VERSION 5.8 ;
BUSBITCHARS "[]" ;
DIVIDERCHAR "/" ;
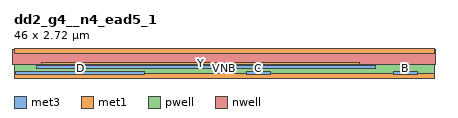
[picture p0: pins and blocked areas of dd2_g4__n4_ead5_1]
MACRO dd2_g4__n4_ead5_1
  CLASS CORE ;
  ORIGIN 0 0 ;
  SIZE 46.000 BY 2.720 ;
  SYMMETRY X Y ;
  SITE unithd ;
  PIN A
    DIRECTION INPUT ;
    USE SIGNAL ;
    ANTENNAGATEAREA 0.426000 ;
    PORT
      LAYER met3 ;
        RECT 2.485 0.855 39.615 1.185 ;
    END
  END A
  PIN B
    DIRECTION INPUT ;
    USE SIGNAL ;
    ANTENNAGATEAREA 0.213000 ;
    PORT
      LAYER met3 ;
        RECT 41.585 0.175 44.215 0.505 ;
    END
  END B
  PIN C
    DIRECTION INPUT ;
    USE SIGNAL ;
    ANTENNAGATEAREA 0.213000 ;
    PORT
      LAYER met3 ;
        RECT 25.485 0.175 28.115 0.505 ;
    END
  END C
  PIN D
    DIRECTION INPUT ;
    USE SIGNAL ;
    ANTENNAGATEAREA 0.426000 ;
    PORT
      LAYER met3 ;
        RECT 0.185 0.175 14.315 0.505 ;
    END
  END D
  PIN VGND
    DIRECTION INOUT ;
    USE GROUND ;
    SHAPE ABUTMENT ;
    PORT
      LAYER met1 ;
        RECT 0.000 -0.240 46.000 0.240 ;
    END
  END VGND
  PIN VNB
    DIRECTION INOUT ;
    USE GROUND ;
    PORT
      LAYER pwell ;
        RECT 0.000 0.000 46.000 1.305 ;
    END
  END VNB
  PIN VPB
    DIRECTION INOUT ;
    USE POWER ;
    PORT
      LAYER nwell ;
        RECT -0.190 1.305 46.190 2.910 ;
    END
  END VPB
  PIN VPWR
    DIRECTION INOUT ;
    USE POWER ;
    SHAPE ABUTMENT ;
    PORT
      LAYER met1 ;
        RECT 0.000 2.480 46.000 2.960 ;
    END
  END VPWR
  PIN Y
    DIRECTION OUTPUT ;
    USE SIGNAL ;
    ANTENNADIFFAREA 1.305600 ;
    PORT
      LAYER met1 ;
        RECT 3.065 1.230 3.385 1.290 ;
        RECT 9.965 1.230 10.285 1.290 ;
        RECT 12.265 1.230 12.585 1.290 ;
        RECT 19.165 1.230 19.485 1.290 ;
        RECT 37.565 1.230 37.885 1.290 ;
        RECT 3.060 1.290 37.890 1.430 ;
        RECT 3.065 1.430 3.385 1.490 ;
        RECT 9.965 1.430 10.285 1.490 ;
        RECT 12.265 1.430 12.585 1.490 ;
        RECT 19.165 1.430 19.485 1.490 ;
        RECT 37.565 1.430 37.885 1.490 ;
    END
  END Y
  OBS
    LAYER li1 ;
      RECT 0.000 -0.085 46.000 0.085 ;
      RECT 0.000 2.635 46.000 2.805 ;
      RECT 29.090 0.085 29.260 0.255 ;
      RECT 42.890 0.085 43.060 0.255 ;
      RECT 24.410 0.255 24.740 0.635 ;
      RECT 29.010 0.255 29.340 0.635 ;
      RECT 42.810 0.255 43.140 0.635 ;
      RECT 23.910 0.255 24.240 0.380 ;
      RECT 23.760 0.380 24.240 0.710 ;
      RECT 28.510 0.255 28.840 0.380 ;
      RECT 28.360 0.380 28.840 0.710 ;
      RECT 30.810 0.255 31.140 0.380 ;
      RECT 30.660 0.380 31.140 0.710 ;
      RECT 31.310 0.255 31.640 0.380 ;
      RECT 31.310 0.380 31.680 0.710 ;
      RECT 35.410 0.255 35.740 0.380 ;
      RECT 35.260 0.380 35.740 0.710 ;
      RECT 35.910 0.255 36.240 0.380 ;
      RECT 35.910 0.380 36.280 0.710 ;
      RECT 42.310 0.255 42.640 0.380 ;
      RECT 42.160 0.380 42.640 0.710 ;
      RECT 23.165 0.380 23.515 0.710 ;
      RECT 23.165 0.710 23.335 1.075 ;
      RECT 23.165 1.075 24.340 1.315 ;
      RECT 25.465 0.380 25.815 0.710 ;
      RECT 25.465 0.710 25.635 1.075 ;
      RECT 25.465 1.075 26.640 1.315 ;
      RECT 27.765 0.380 28.115 0.710 ;
      RECT 27.765 0.710 27.935 1.075 ;
      RECT 27.765 1.075 28.940 1.315 ;
      RECT 30.065 0.380 30.415 0.710 ;
      RECT 30.065 0.710 30.235 1.075 ;
      RECT 30.065 1.075 31.240 1.315 ;
      RECT 32.365 0.380 32.715 0.710 ;
      RECT 32.365 0.710 32.535 1.075 ;
      RECT 32.365 1.075 33.540 1.315 ;
      RECT 34.665 0.380 35.015 0.710 ;
      RECT 34.665 0.710 34.835 1.075 ;
      RECT 34.665 1.075 35.840 1.315 ;
      RECT 36.965 0.380 37.315 0.710 ;
      RECT 36.965 0.710 37.135 1.075 ;
      RECT 36.965 1.075 38.140 1.315 ;
      RECT 39.265 0.380 39.615 0.710 ;
      RECT 39.265 0.710 39.435 1.075 ;
      RECT 39.265 1.075 40.440 1.315 ;
      RECT 41.565 0.380 41.915 0.710 ;
      RECT 41.565 0.710 41.735 1.075 ;
      RECT 41.565 1.075 42.740 1.315 ;
      RECT 43.865 0.380 44.215 0.710 ;
      RECT 43.865 0.710 44.035 1.075 ;
      RECT 43.865 1.075 45.040 1.315 ;
      RECT 26.210 1.505 26.540 2.010 ;
      RECT 26.060 2.010 26.540 2.340 ;
      RECT 26.210 2.340 26.540 2.465 ;
      RECT 33.110 1.505 33.440 2.010 ;
      RECT 32.960 2.010 33.440 2.340 ;
      RECT 33.110 2.340 33.440 2.465 ;
      RECT 37.710 1.505 38.040 2.010 ;
      RECT 37.560 2.010 38.040 2.340 ;
      RECT 37.710 2.340 38.040 2.465 ;
      RECT 38.210 1.505 38.540 2.010 ;
      RECT 38.210 2.010 38.580 2.340 ;
      RECT 38.210 2.340 38.540 2.465 ;
      RECT 40.010 1.505 40.340 2.010 ;
      RECT 39.860 2.010 40.340 2.340 ;
      RECT 40.010 2.340 40.340 2.465 ;
      RECT 44.610 1.505 44.940 2.010 ;
      RECT 44.460 2.010 44.940 2.340 ;
      RECT 44.610 2.340 44.940 2.465 ;
      RECT 26.710 1.505 27.040 2.465 ;
      RECT 33.610 1.505 33.940 2.465 ;
      RECT 40.510 1.505 40.840 2.465 ;
      RECT 45.110 1.505 45.440 2.465 ;
      RECT 26.790 2.465 26.960 2.635 ;
      RECT 33.690 2.465 33.860 2.635 ;
      RECT 40.590 2.465 40.760 2.635 ;
      RECT 45.190 2.465 45.360 2.635 ;
      RECT 24.490 0.085 24.660 0.255 ;
      RECT 15.210 0.255 15.540 0.635 ;
      RECT 17.510 0.255 17.840 0.635 ;
      RECT 8.390 0.085 8.560 0.255 ;
      RECT 15.290 0.085 15.460 0.255 ;
      RECT 17.590 0.085 17.760 0.255 ;
      RECT 3.210 0.255 3.540 0.380 ;
      RECT 3.060 0.380 3.540 0.710 ;
      RECT 3.710 0.255 4.040 0.380 ;
      RECT 3.710 0.380 4.080 0.710 ;
      RECT 7.810 0.255 8.140 0.380 ;
      RECT 7.660 0.380 8.140 0.710 ;
      RECT 10.110 0.255 10.440 0.380 ;
      RECT 9.960 0.380 10.440 0.710 ;
      RECT 0.165 0.380 0.515 0.710 ;
      RECT 0.165 0.710 0.335 1.075 ;
      RECT 0.165 1.075 1.340 1.315 ;
      RECT 2.465 0.380 2.815 0.710 ;
      RECT 2.465 0.710 2.635 1.075 ;
      RECT 2.465 1.075 3.640 1.315 ;
      RECT 4.765 0.380 5.115 0.710 ;
      RECT 4.765 0.710 4.935 1.075 ;
      RECT 4.765 1.075 5.940 1.315 ;
      RECT 7.065 0.380 7.415 0.710 ;
      RECT 0.910 1.505 1.240 2.010 ;
      RECT 0.760 2.010 1.240 2.340 ;
      RECT 0.910 2.340 1.240 2.465 ;
      RECT 5.510 1.505 5.840 2.010 ;
      RECT 5.360 2.010 5.840 2.340 ;
      RECT 5.510 2.340 5.840 2.465 ;
      RECT 12.410 1.505 12.740 2.010 ;
      RECT 12.260 2.010 12.740 2.340 ;
      RECT 12.410 2.340 12.740 2.465 ;
      RECT 12.910 1.505 13.240 2.010 ;
      RECT 12.910 2.010 13.280 2.340 ;
      RECT 12.910 2.340 13.240 2.465 ;
      RECT 19.310 1.505 19.640 2.010 ;
      RECT 19.160 2.010 19.640 2.340 ;
      RECT 19.310 2.340 19.640 2.465 ;
      RECT 19.810 1.505 20.140 2.010 ;
      RECT 19.810 2.010 20.180 2.340 ;
      RECT 19.810 2.340 20.140 2.465 ;
      RECT 21.610 1.505 21.940 2.010 ;
      RECT 21.460 2.010 21.940 2.340 ;
      RECT 21.610 2.340 21.940 2.465 ;
      RECT 7.065 0.710 7.235 1.075 ;
      RECT 7.065 1.075 8.240 1.315 ;
      RECT 9.365 0.380 9.715 0.710 ;
      RECT 9.365 0.710 9.535 1.075 ;
      RECT 9.365 1.075 10.540 1.315 ;
      RECT 11.665 0.380 12.015 0.710 ;
      RECT 11.665 0.710 11.835 1.075 ;
      RECT 11.665 1.075 12.840 1.315 ;
      RECT 13.965 0.380 14.315 0.710 ;
      RECT 13.965 0.710 14.135 1.075 ;
      RECT 13.965 1.075 15.140 1.315 ;
      RECT 16.265 0.380 16.615 0.710 ;
      RECT 16.265 0.710 16.435 1.075 ;
      RECT 16.265 1.075 17.440 1.315 ;
      RECT 18.565 0.380 18.915 0.710 ;
      RECT 18.565 0.710 18.735 1.075 ;
      RECT 18.565 1.075 19.740 1.315 ;
      RECT 20.865 0.380 21.215 0.710 ;
      RECT 1.410 1.505 1.740 2.465 ;
      RECT 6.010 1.505 6.340 2.465 ;
      RECT 22.110 1.505 22.440 2.465 ;
      RECT 20.865 0.710 21.035 1.075 ;
      RECT 20.865 1.075 22.040 1.315 ;
      RECT 10.610 0.255 10.940 0.380 ;
      RECT 10.610 0.380 10.980 0.710 ;
      RECT 1.490 2.465 1.660 2.635 ;
      RECT 6.090 2.465 6.260 2.635 ;
      RECT 22.190 2.465 22.360 2.635 ;
      RECT 14.710 0.255 15.040 0.380 ;
      RECT 14.560 0.380 15.040 0.710 ;
      RECT 17.010 0.255 17.340 0.380 ;
      RECT 16.860 0.380 17.340 0.710 ;
      RECT 8.310 0.255 8.640 0.635 ;
    LAYER met1 ;
      RECT 0.185 0.380 0.515 0.710 ;
      RECT 2.485 0.380 2.815 0.710 ;
      RECT 3.060 0.380 3.390 0.710 ;
      RECT 3.750 0.380 4.080 0.710 ;
      RECT 4.785 0.380 5.115 0.710 ;
      RECT 7.085 0.380 7.415 0.710 ;
      RECT 7.660 0.380 7.990 0.710 ;
      RECT 9.385 0.380 9.715 0.710 ;
      RECT 9.960 0.380 10.290 0.710 ;
      RECT 10.650 0.380 10.980 0.710 ;
      RECT 11.685 0.380 12.015 0.710 ;
      RECT 13.985 0.380 14.315 0.710 ;
      RECT 14.560 0.380 14.890 0.710 ;
      RECT 16.285 0.380 16.615 0.710 ;
      RECT 18.585 0.380 18.915 0.710 ;
      RECT 20.885 0.380 21.215 0.710 ;
      RECT 23.185 0.380 23.515 0.710 ;
      RECT 25.485 0.380 25.815 0.710 ;
      RECT 27.785 0.380 28.115 0.710 ;
      RECT 28.360 0.380 28.690 0.710 ;
      RECT 30.085 0.380 30.415 0.710 ;
      RECT 30.660 0.380 30.990 0.710 ;
      RECT 32.385 0.380 32.715 0.710 ;
      RECT 34.685 0.380 35.015 0.710 ;
      RECT 35.260 0.380 35.590 0.710 ;
      RECT 36.985 0.380 37.315 0.710 ;
      RECT 39.285 0.380 39.615 0.710 ;
      RECT 41.585 0.380 41.915 0.710 ;
      RECT 42.160 0.380 42.490 0.710 ;
      RECT 43.885 0.380 44.215 0.710 ;
      RECT 0.765 0.790 1.085 0.850 ;
      RECT 12.955 0.790 13.275 0.850 ;
      RECT 0.760 0.850 13.280 0.990 ;
      RECT 0.765 0.990 1.085 1.050 ;
      RECT 12.955 0.990 13.275 1.050 ;
      RECT 16.860 0.380 17.190 0.710 ;
      RECT 23.760 0.380 24.090 0.710 ;
      RECT 31.350 0.380 31.680 0.710 ;
      RECT 35.950 0.380 36.280 0.710 ;
      RECT 16.865 0.710 17.185 0.850 ;
      RECT 23.765 0.710 24.085 0.850 ;
      RECT 31.355 0.710 31.675 0.850 ;
      RECT 35.955 0.710 36.275 0.850 ;
      RECT 16.860 0.850 36.280 0.990 ;
      RECT 16.865 0.990 17.185 1.050 ;
      RECT 23.765 0.990 24.085 1.050 ;
      RECT 31.355 0.990 31.675 1.050 ;
      RECT 35.955 0.990 36.275 1.050 ;
      RECT 3.755 1.670 4.075 1.730 ;
      RECT 10.655 1.670 10.975 1.730 ;
      RECT 30.665 1.670 30.985 1.730 ;
      RECT 35.265 1.670 35.585 1.730 ;
      RECT 3.750 1.730 35.590 1.870 ;
      RECT 3.755 1.870 4.075 1.930 ;
      RECT 10.655 1.870 10.975 1.930 ;
      RECT 30.665 1.870 30.985 1.930 ;
      RECT 35.265 1.870 35.585 1.930 ;
      RECT 0.760 2.010 1.090 2.340 ;
      RECT 5.360 2.010 5.690 2.340 ;
      RECT 12.260 2.010 12.590 2.340 ;
      RECT 12.950 2.010 13.280 2.340 ;
      RECT 19.160 2.010 19.490 2.340 ;
      RECT 19.850 2.010 20.180 2.340 ;
      RECT 21.460 2.010 21.790 2.340 ;
      RECT 26.060 2.010 26.390 2.340 ;
      RECT 32.960 2.010 33.290 2.340 ;
      RECT 37.560 2.010 37.890 2.340 ;
      RECT 38.250 2.010 38.580 2.340 ;
      RECT 39.860 2.010 40.190 2.340 ;
      RECT 44.460 2.010 44.790 2.340 ;
    LAYER met2 ;
      RECT 0.210 0.155 0.490 0.210 ;
      RECT 0.190 0.210 0.510 0.675 ;
      RECT 4.810 0.155 5.090 0.210 ;
      RECT 4.790 0.210 5.110 0.675 ;
      RECT 9.410 0.155 9.690 0.210 ;
      RECT 9.390 0.210 9.710 0.675 ;
      RECT 14.010 0.155 14.290 0.210 ;
      RECT 13.990 0.210 14.310 0.675 ;
      RECT 25.510 0.155 25.790 0.210 ;
      RECT 25.490 0.210 25.810 0.675 ;
      RECT 27.810 0.155 28.090 0.210 ;
      RECT 27.790 0.210 28.110 0.675 ;
      RECT 41.610 0.155 41.890 0.210 ;
      RECT 41.590 0.210 41.910 0.675 ;
      RECT 43.910 0.155 44.190 0.210 ;
      RECT 43.890 0.210 44.210 0.675 ;
      RECT 16.865 0.415 17.185 1.050 ;
      RECT 23.765 0.415 24.085 1.050 ;
      RECT 31.355 0.415 31.675 1.050 ;
      RECT 35.955 0.415 36.275 1.050 ;
      RECT 2.490 0.415 2.810 1.150 ;
      RECT 2.510 1.150 2.790 1.205 ;
      RECT 7.090 0.415 7.410 1.150 ;
      RECT 7.110 1.150 7.390 1.205 ;
      RECT 11.690 0.415 12.010 1.150 ;
      RECT 11.710 1.150 11.990 1.205 ;
      RECT 39.290 0.415 39.610 1.150 ;
      RECT 39.310 1.150 39.590 1.205 ;
      RECT 3.065 0.415 3.385 1.490 ;
      RECT 9.965 0.415 10.285 1.490 ;
      RECT 14.565 0.415 14.885 1.830 ;
      RECT 14.585 1.830 14.865 1.885 ;
      RECT 20.890 0.415 21.210 1.830 ;
      RECT 20.910 1.830 21.190 1.885 ;
      RECT 23.190 0.415 23.510 1.830 ;
      RECT 23.210 1.830 23.490 1.885 ;
      RECT 28.365 0.415 28.685 1.830 ;
      RECT 28.385 1.830 28.665 1.885 ;
      RECT 30.090 0.415 30.410 1.830 ;
      RECT 30.110 1.830 30.390 1.885 ;
      RECT 32.390 0.415 32.710 1.830 ;
      RECT 32.410 1.830 32.690 1.885 ;
      RECT 34.690 0.415 35.010 1.830 ;
      RECT 34.710 1.830 34.990 1.885 ;
      RECT 36.990 0.415 37.310 1.830 ;
      RECT 37.010 1.830 37.290 1.885 ;
      RECT 42.165 0.415 42.485 1.830 ;
      RECT 42.185 1.830 42.465 1.885 ;
      RECT 3.755 0.415 4.075 1.930 ;
      RECT 10.655 0.415 10.975 1.930 ;
      RECT 30.665 0.415 30.985 1.930 ;
      RECT 35.265 0.415 35.585 1.930 ;
      RECT 0.765 0.790 1.085 2.305 ;
      RECT 5.385 1.515 5.665 1.570 ;
      RECT 5.365 1.570 5.685 2.305 ;
      RECT 12.265 1.230 12.585 2.305 ;
      RECT 12.955 0.790 13.275 2.305 ;
      RECT 19.165 1.230 19.485 2.305 ;
      RECT 19.875 0.155 20.155 0.210 ;
      RECT 19.855 0.210 20.175 2.305 ;
      RECT 21.485 0.155 21.765 0.210 ;
      RECT 21.465 0.210 21.785 2.305 ;
      RECT 26.085 1.515 26.365 1.570 ;
      RECT 26.065 1.570 26.385 2.305 ;
      RECT 32.985 0.155 33.265 0.210 ;
      RECT 32.965 0.210 33.285 2.305 ;
      RECT 37.565 1.230 37.885 2.305 ;
      RECT 38.275 0.155 38.555 0.210 ;
      RECT 38.255 0.210 38.575 2.305 ;
      RECT 44.485 1.515 44.765 1.570 ;
      RECT 44.465 1.570 44.785 2.305 ;
      RECT 7.665 0.415 7.985 2.510 ;
      RECT 7.685 2.510 7.965 2.565 ;
      RECT 16.290 0.415 16.610 2.510 ;
      RECT 16.310 2.510 16.590 2.565 ;
      RECT 18.590 0.415 18.910 2.510 ;
      RECT 18.610 2.510 18.890 2.565 ;
      RECT 39.865 2.045 40.185 2.510 ;
      RECT 39.885 2.510 40.165 2.565 ;
    LAYER met3 ;
      RECT 19.850 0.175 21.790 0.505 ;
      RECT 32.960 0.175 38.580 0.505 ;
      RECT 5.360 1.535 23.515 1.865 ;
      RECT 26.060 1.535 32.715 1.865 ;
      RECT 34.685 1.535 44.790 1.865 ;
      RECT 7.660 2.215 40.190 2.545 ;
  END
END dd2_g4__n4_ead5_1
END LIBRARY
